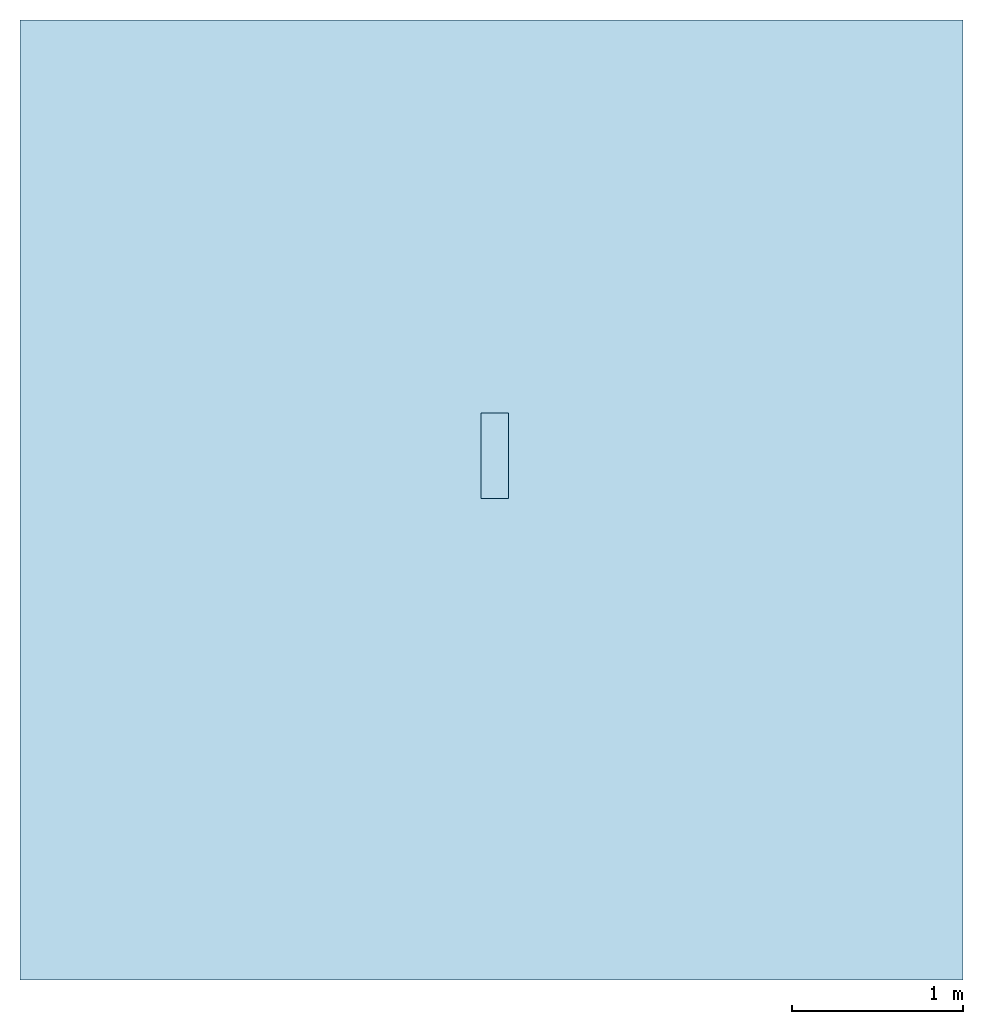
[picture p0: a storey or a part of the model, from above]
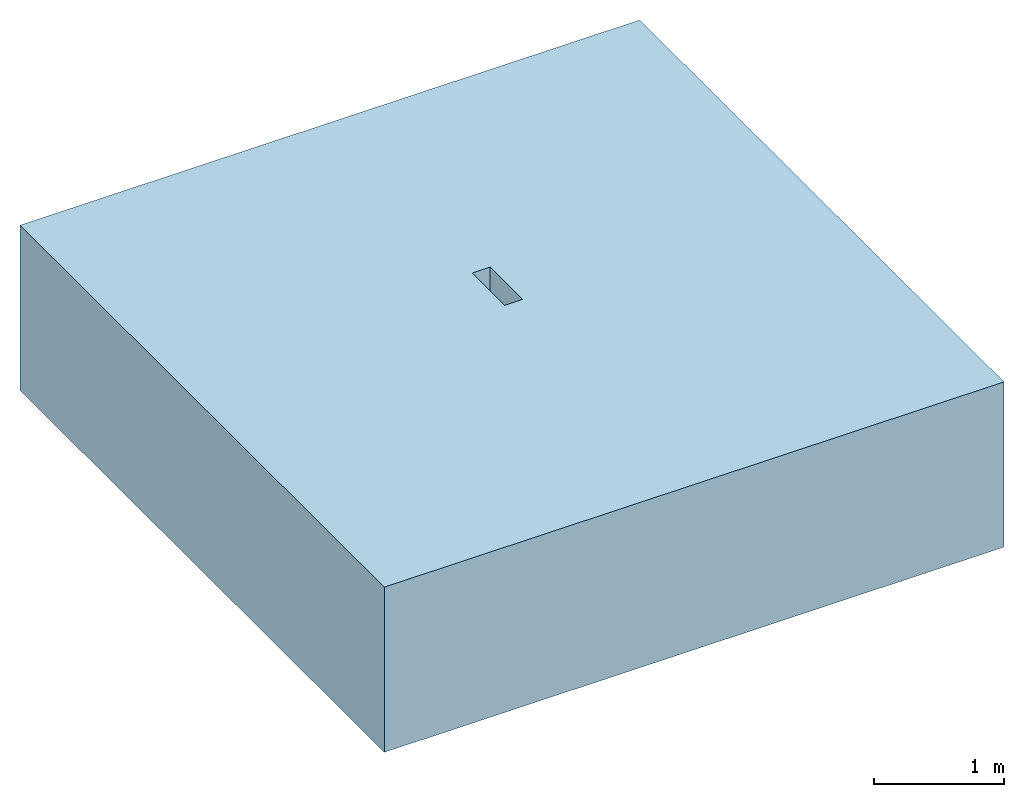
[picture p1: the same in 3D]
Properties of the parts of a building model (IFC2X3)

# File
Description: ViewDefinition [CoordinationView]
File name: 32401 - PD100 F 40.1 Channel 500mm LG.ifc
Time: 2013-10-11T12:32:49
Written by: Autodesk Revit 2013
Made in: 20120221_2030(x64)

# IfcProject, Project Number
LongName: Project Name; Phase: Project Status

# IfcSite, Default
RefLatitude: 42, 21, 30, 344238; RefLongitude: -71, -3, -35, -194702; RefElevation: 0 mm

# IfcBuilding
Pset_BuildingCommon - NumberOfStoreys: 2
Other - Project Status: Project Status; Client Name: Owner; Project Address: Enter address here; Project Issue Date: Issue Date; Project Name: Project Name; Project Number: Project Number

# IfcBuildingStorey (2)
Constraints - Elevation Base: 0
Graphics - Symbol at End 1 Default: no; Symbol at End 2 Default: yes; Symbol: M_Level Head - Circle: M_Level Head - Circle; Line Pattern: Center; Line Weight: 1; Color: 0
Identity Data - Structural: no; Building Story: yes
Dimensions - Computation Height: 0 mm
Name | LongName = Name | Elevation (mm) = Constraints, Elevation (mm)
B.O. Footing | B.O. Footing | -4600
T.O. Footing | T.O. Footing | -4300

# IfcBuildingElementProxy: 32401 - PD100 F 40.1 Channel 500mm LG, Civil-Drainage-Channel-ACO-RoadDrain 100:32401 - PD100 F 40.1 Channel 500mm LG:32401 - PD100 F 40.1 Channel 500mm LG:310733
In: B.O. Footing
Material: Acetal Resin, Black
Other - CreatedBy: www.aco.co.uk; Revision: 1
Dimensions - Void Depth: -400 mm; Total Depth: 400 mm; Straight Void Start: 0 mm; I/O End Cap Void: 3250 mm; Invert Depth.: 325 mm; Length: 500 mm; Straight Void Length: 500 mm; Custom Void Length: 0 mm; Volume: 17119163 mm3
Phasing - Phase Created: Phase 1
Constraints - Level: Level: T.O. Footing; Moves With Nearby Elements: no
Pset_BuildingElementProxyCommon - Reference: 32401 - PD100 F 40.1 Channel 500mm LG
Materials and Finishes - Channel Colour: Black; Channel Material: Vienite® Synthetic Resin Concrete; Connection Pipe Colour: N/A; Access Cover/Frame Material: N/A; End Cap Material: N/A; End Cap Colour: N/A; Grating Material: N/A; Connection Pipe Material: N/A; Grating Finish: N/A; Access Cover/Frame Colour: N/A; Grating Colour: N/A; Access Cover/Frame Finish: N/A
Identity Data - e-mail Technical: technical@aco.co.uk; Maintenance guidelines: http://www.aco.co.uk/download.php?id=256; Price: POA - contact ACO; Cost: 0; Product Code: 32401; Watermarked With: BIM Manager Premium Suite; Address: ACO Business Park, Hitchin Road, Shefford, Bedfordshire, United Kingdom SG17 5TE; Product brochure: http://www.aco.co.uk/download.php?id=256; Model Description: Monolithic Channel drainage system; Assembly Code: D2040; Installation guidelines: http://www.aco.co.uk/download.php?id=256; Fax: +44 (0)1462 815895; Watermarked By: www.aco.co.uk; Watermark 2: This file is water marked and users are prohibited to reproduce, adapt, distribute this information; Telephone: +44 (0)1462 816666; Watermark 1: This file is the property of ACO Technologies PLC; Type Comments: ACO RoadDrain 100 PD100F 40.1 Constant Depth Channel 500mm Long; e-mail Sales: customersupport@aco.co.uk; Manufacturer: ACO Technologies plc - ACO Water Management Division ACO Technologies plc - ACO Water Management Division; URL: www.aco.co.uk; OmniClass Number: 23.70.50.24; Product Page URL: http://www.aco.co.uk/product_detail.php?id=21; OmniClass Title: Rainwater Removal; Assembly Description: Rain Water Drainage; Model: ACO RoadDrain 100 PD100F
Construction - Closing End Cap: no; Inlet Outlet end cap_350 high: no; Inlet Outlet end cap_450 high: no; Channel 160mm Wide: yes; Access unit: no; Grating 500mm: no; 32900 - Sump Unit: no
Data - Channel C.S.A: 0.027m²; Connection Pipe O.D: N/A; ACO Hydraulic Design Software: http://www.acodesign.co.uk; Installation - Concrete Grade: Refer to brochure; Load Class: A 15 - F 900; Product Standard: BE EN1433:2002, CE Marked, Kitemarked; Product Dimensions: 500mm x 160mm x 400mm (LxWxH); Concrete Surround Volume - Load Class F 900 - Concrete Pavement: 0.28m³; Invert Depth: 375mm; Product Weight: 28.6 Kg; Hydraulic Performance: http://www.aco.co.uk/download.php?id=256
General - SerialNumber: 0.000000; TagNumber: 0.000000
Green Building Properties - Access Cover/Frame Recycled Material Content: N/A; Grating Recyclable: Fully recyclable; Grating Recycled Material Content: Between 40% - 90%; End Cap Recycled Material Content: N/A; End Cap Recyclable: N/A; Channel Recycled Material Content: 20% minimum; Channel Recyclable: Fully recyclable; Access Cover/Frame Recyclable: N/A

# IfcOpeningElement: Recess (2)
In: T.O. Footing
Constraints - Related to Mass: no; Height Offset From Level: 0 mm; Level: Level: T.O. Footing; Room Bounding: yes
Phasing - Phase Created: Phase 1
Structural - Enable Analytical Model: no; Structural: no
Dimensions - Thickness: 1550 mm; Perimeter: 22200 mm; Volume: 47708000000 mm3; Area: 30800000 mm2
Graphics - Coarse Scale Fill Color: 0
Analytical Properties - Thermal Resistance (R): 1.79211; Roughness: 1; Absorptance: 0.1; Heat Transfer Coefficient (U): 0.558; Thermal mass: 2039700
Construction - Function: 0; Default Thickness: 1550 mm
Materials and Finishes - Structural Material: Grass

# IfcSlab: Floor:Generic Floor - 400mm, Floor:Generic Floor - 400mm:136436
In: T.O. Footing
PredefinedType: FLOOR; Material: Grass 50 mm, Earth 1500 mm
Constraints - Related to Mass: no; Height Offset From Level: 0 mm; Level: Level: T.O. Footing; Room Bounding: yes
Phasing - Phase Created: Phase 1
Structural - Enable Analytical Model: no; Structural: no
Dimensions - Thickness: 1550 mm; Perimeter: 22200 mm; Volume: 47708000000 mm3; Area: 30800000 mm2
Pset_SlabCommon - Reference: Generic Floor - 400mm; IsExternal: no; LoadBearing: yes
Graphics - Coarse Scale Fill Color: 0
Analytical Properties - Thermal Resistance (R): 1.79211; Roughness: 1; Absorptance: 0.1; Heat Transfer Coefficient (U): 0.558; Thermal mass: 2039700
Construction - Function: 0; Default Thickness: 1550 mm
Materials and Finishes - Structural Material: Grass
